VERSION 5.7 ;
  NOWIREEXTENSIONATPIN ON ;
  DIVIDERCHAR "/" ;
  BUSBITCHARS "[]" ;
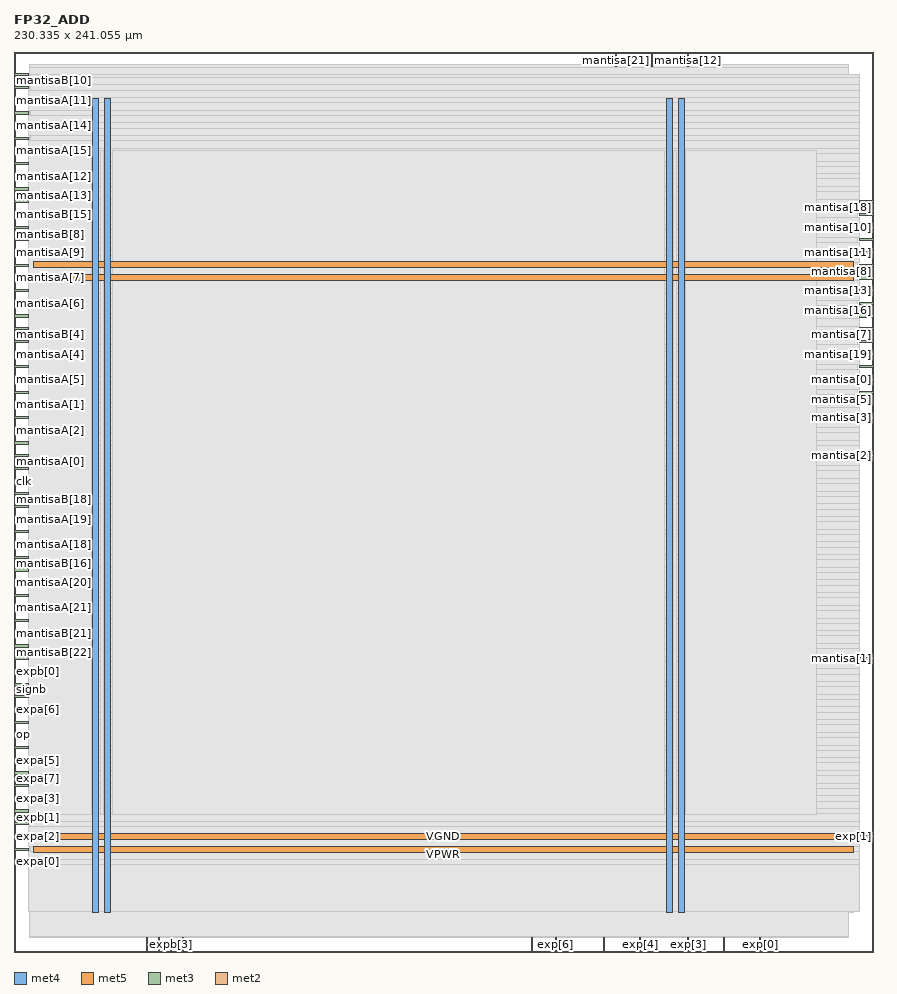
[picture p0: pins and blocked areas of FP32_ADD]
MACRO FP32_ADD
  CLASS BLOCK ;
  FOREIGN FP32_ADD ;
  ORIGIN 0.000 0.000 ;
  SIZE 230.335 BY 241.055 ;
  PIN VGND
    DIRECTION INOUT ;
    USE GROUND ;
    PORT
      LAYER met4 ;
        RECT 24.340 10.640 25.940 228.720 ;
    END
    PORT
      LAYER met4 ;
        RECT 177.940 10.640 179.540 228.720 ;
    END
    PORT
      LAYER met5 ;
        RECT 5.280 30.030 224.720 31.630 ;
    END
    PORT
      LAYER met5 ;
        RECT 5.280 183.210 224.720 184.810 ;
    END
  END VGND
  PIN VPWR
    DIRECTION INOUT ;
    USE POWER ;
    PORT
      LAYER met4 ;
        RECT 21.040 10.640 22.640 228.720 ;
    END
    PORT
      LAYER met4 ;
        RECT 174.640 10.640 176.240 228.720 ;
    END
    PORT
      LAYER met5 ;
        RECT 5.280 26.730 224.720 28.330 ;
    END
    PORT
      LAYER met5 ;
        RECT 5.280 179.910 224.720 181.510 ;
    END
  END VPWR
  PIN clk
    DIRECTION INPUT ;
    USE SIGNAL ;
    ANTENNAGATEAREA 0.852000 ;
    PORT
      LAYER met3 ;
        RECT 0.000 125.840 4.000 126.440 ;
    END
  END clk
  PIN exp[0]
    DIRECTION OUTPUT ;
    USE SIGNAL ;
    ANTENNADIFFAREA 0.445500 ;
    PORT
      LAYER met2 ;
        RECT 199.730 0.000 200.010 4.000 ;
    END
  END exp[0]
  PIN exp[1]
    DIRECTION OUTPUT ;
    USE SIGNAL ;
    ANTENNADIFFAREA 0.445500 ;
    PORT
      LAYER met3 ;
        RECT 226.335 30.640 230.335 31.240 ;
    END
  END exp[1]
  PIN exp[2]
    DIRECTION OUTPUT ;
    USE SIGNAL ;
    ANTENNADIFFAREA 0.445500 ;
    PORT
      LAYER met2 ;
        RECT 190.070 0.000 190.350 4.000 ;
    END
  END exp[2]
  PIN exp[3]
    DIRECTION OUTPUT ;
    USE SIGNAL ;
    ANTENNADIFFAREA 0.445500 ;
    PORT
      LAYER met2 ;
        RECT 180.410 0.000 180.690 4.000 ;
    END
  END exp[3]
  PIN exp[4]
    DIRECTION OUTPUT ;
    USE SIGNAL ;
    ANTENNADIFFAREA 0.445500 ;
    PORT
      LAYER met2 ;
        RECT 167.530 0.000 167.810 4.000 ;
    END
  END exp[4]
  PIN exp[5]
    DIRECTION OUTPUT ;
    USE SIGNAL ;
    ANTENNADIFFAREA 0.445500 ;
    PORT
      LAYER met2 ;
        RECT 157.870 0.000 158.150 4.000 ;
    END
  END exp[5]
  PIN exp[6]
    DIRECTION OUTPUT ;
    USE SIGNAL ;
    ANTENNADIFFAREA 0.445500 ;
    PORT
      LAYER met2 ;
        RECT 144.990 0.000 145.270 4.000 ;
    END
  END exp[6]
  PIN exp[7]
    DIRECTION OUTPUT ;
    USE SIGNAL ;
    ANTENNADIFFAREA 0.445500 ;
    PORT
      LAYER met2 ;
        RECT 138.550 0.000 138.830 4.000 ;
    END
  END exp[7]
  PIN expa[0]
    DIRECTION INPUT ;
    USE SIGNAL ;
    ANTENNAGATEAREA 0.196500 ;
    PORT
      LAYER met3 ;
        RECT 0.000 23.840 4.000 24.440 ;
    END
  END expa[0]
  PIN expa[1]
    DIRECTION INPUT ;
    USE SIGNAL ;
    ANTENNAGATEAREA 0.196500 ;
    PORT
      LAYER met3 ;
        RECT 0.000 27.240 4.000 27.840 ;
    END
  END expa[1]
  PIN expa[2]
    DIRECTION INPUT ;
    USE SIGNAL ;
    ANTENNAGATEAREA 0.196500 ;
    PORT
      LAYER met3 ;
        RECT 0.000 30.640 4.000 31.240 ;
    END
  END expa[2]
  PIN expa[3]
    DIRECTION INPUT ;
    USE SIGNAL ;
    ANTENNAGATEAREA 0.126000 ;
    PORT
      LAYER met3 ;
        RECT 0.000 40.840 4.000 41.440 ;
    END
  END expa[3]
  PIN expa[4]
    DIRECTION INPUT ;
    USE SIGNAL ;
    ANTENNAGATEAREA 0.196500 ;
    PORT
      LAYER met2 ;
        RECT 35.510 0.000 35.790 4.000 ;
    END
  END expa[4]
  PIN expa[5]
    DIRECTION INPUT ;
    USE SIGNAL ;
    ANTENNAGATEAREA 0.196500 ;
    PORT
      LAYER met3 ;
        RECT 0.000 51.040 4.000 51.640 ;
    END
  END expa[5]
  PIN expa[6]
    DIRECTION INPUT ;
    USE SIGNAL ;
    ANTENNAGATEAREA 0.196500 ;
    PORT
      LAYER met3 ;
        RECT 0.000 64.640 4.000 65.240 ;
    END
  END expa[6]
  PIN expa[7]
    DIRECTION INPUT ;
    USE SIGNAL ;
    ANTENNAGATEAREA 0.196500 ;
    PORT
      LAYER met3 ;
        RECT 0.000 44.240 4.000 44.840 ;
    END
  END expa[7]
  PIN expb[0]
    DIRECTION INPUT ;
    USE SIGNAL ;
    ANTENNAGATEAREA 0.196500 ;
    PORT
      LAYER met3 ;
        RECT 0.000 74.840 4.000 75.440 ;
    END
  END expb[0]
  PIN expb[1]
    DIRECTION INPUT ;
    USE SIGNAL ;
    ANTENNAGATEAREA 0.196500 ;
    PORT
      LAYER met3 ;
        RECT 0.000 37.440 4.000 38.040 ;
    END
  END expb[1]
  PIN expb[2]
    DIRECTION INPUT ;
    USE SIGNAL ;
    ANTENNAGATEAREA 0.196500 ;
    PORT
      LAYER met2 ;
        RECT 38.730 0.000 39.010 4.000 ;
    END
  END expb[2]
  PIN expb[3]
    DIRECTION INPUT ;
    USE SIGNAL ;
    ANTENNAGATEAREA 0.196500 ;
    PORT
      LAYER met2 ;
        RECT 41.950 0.000 42.230 4.000 ;
    END
  END expb[3]
  PIN expb[4]
    DIRECTION INPUT ;
    USE SIGNAL ;
    ANTENNAGATEAREA 0.196500 ;
    PORT
      LAYER met2 ;
        RECT 45.170 0.000 45.450 4.000 ;
    END
  END expb[4]
  PIN expb[5]
    DIRECTION INPUT ;
    USE SIGNAL ;
    ANTENNAGATEAREA 0.196500 ;
    PORT
      LAYER met3 ;
        RECT 0.000 54.440 4.000 55.040 ;
    END
  END expb[5]
  PIN expb[6]
    DIRECTION INPUT ;
    USE SIGNAL ;
    ANTENNAGATEAREA 0.196500 ;
    PORT
      LAYER met3 ;
        RECT 0.000 61.240 4.000 61.840 ;
    END
  END expb[6]
  PIN expb[7]
    DIRECTION INPUT ;
    USE SIGNAL ;
    ANTENNAGATEAREA 0.196500 ;
    PORT
      LAYER met3 ;
        RECT 0.000 47.640 4.000 48.240 ;
    END
  END expb[7]
  PIN mantisaA[0]
    DIRECTION INPUT ;
    USE SIGNAL ;
    ANTENNAGATEAREA 0.196500 ;
    PORT
      LAYER met3 ;
        RECT 0.000 129.240 4.000 129.840 ;
    END
  END mantisaA[0]
  PIN mantisaA[10]
    DIRECTION INPUT ;
    USE SIGNAL ;
    ANTENNAGATEAREA 0.126000 ;
    PORT
      LAYER met3 ;
        RECT 0.000 234.640 4.000 235.240 ;
    END
  END mantisaA[10]
  PIN mantisaA[11]
    DIRECTION INPUT ;
    USE SIGNAL ;
    ANTENNAGATEAREA 0.126000 ;
    PORT
      LAYER met3 ;
        RECT 0.000 227.840 4.000 228.440 ;
    END
  END mantisaA[11]
  PIN mantisaA[12]
    DIRECTION INPUT ;
    USE SIGNAL ;
    ANTENNAGATEAREA 0.196500 ;
    PORT
      LAYER met3 ;
        RECT 0.000 207.440 4.000 208.040 ;
    END
  END mantisaA[12]
  PIN mantisaA[13]
    DIRECTION INPUT ;
    USE SIGNAL ;
    ANTENNAGATEAREA 0.196500 ;
    PORT
      LAYER met3 ;
        RECT 0.000 204.040 4.000 204.640 ;
    END
  END mantisaA[13]
  PIN mantisaA[14]
    DIRECTION INPUT ;
    USE SIGNAL ;
    ANTENNAGATEAREA 0.196500 ;
    PORT
      LAYER met3 ;
        RECT 0.000 221.040 4.000 221.640 ;
    END
  END mantisaA[14]
  PIN mantisaA[15]
    DIRECTION INPUT ;
    USE SIGNAL ;
    ANTENNAGATEAREA 0.196500 ;
    PORT
      LAYER met3 ;
        RECT 0.000 214.240 4.000 214.840 ;
    END
  END mantisaA[15]
  PIN mantisaA[16]
    DIRECTION INPUT ;
    USE SIGNAL ;
    ANTENNAGATEAREA 0.196500 ;
    PORT
      LAYER met3 ;
        RECT 0.000 122.440 4.000 123.040 ;
    END
  END mantisaA[16]
  PIN mantisaA[17]
    DIRECTION INPUT ;
    USE SIGNAL ;
    ANTENNAGATEAREA 0.196500 ;
    PORT
      LAYER met3 ;
        RECT 0.000 112.240 4.000 112.840 ;
    END
  END mantisaA[17]
  PIN mantisaA[18]
    DIRECTION INPUT ;
    USE SIGNAL ;
    ANTENNAGATEAREA 0.196500 ;
    PORT
      LAYER met3 ;
        RECT 0.000 108.840 4.000 109.440 ;
    END
  END mantisaA[18]
  PIN mantisaA[19]
    DIRECTION INPUT ;
    USE SIGNAL ;
    ANTENNAGATEAREA 0.196500 ;
    PORT
      LAYER met3 ;
        RECT 0.000 115.640 4.000 116.240 ;
    END
  END mantisaA[19]
  PIN mantisaA[1]
    DIRECTION INPUT ;
    USE SIGNAL ;
    ANTENNAGATEAREA 0.196500 ;
    PORT
      LAYER met3 ;
        RECT 0.000 146.240 4.000 146.840 ;
    END
  END mantisaA[1]
  PIN mantisaA[20]
    DIRECTION INPUT ;
    USE SIGNAL ;
    ANTENNAGATEAREA 0.196500 ;
    PORT
      LAYER met3 ;
        RECT 0.000 98.640 4.000 99.240 ;
    END
  END mantisaA[20]
  PIN mantisaA[21]
    DIRECTION INPUT ;
    USE SIGNAL ;
    ANTENNAGATEAREA 0.196500 ;
    PORT
      LAYER met3 ;
        RECT 0.000 91.840 4.000 92.440 ;
    END
  END mantisaA[21]
  PIN mantisaA[22]
    DIRECTION INPUT ;
    USE SIGNAL ;
    ANTENNAGATEAREA 0.196500 ;
    PORT
      LAYER met3 ;
        RECT 0.000 88.440 4.000 89.040 ;
    END
  END mantisaA[22]
  PIN mantisaA[2]
    DIRECTION INPUT ;
    USE SIGNAL ;
    ANTENNAGATEAREA 0.196500 ;
    PORT
      LAYER met3 ;
        RECT 0.000 139.440 4.000 140.040 ;
    END
  END mantisaA[2]
  PIN mantisaA[3]
    DIRECTION INPUT ;
    USE SIGNAL ;
    ANTENNAGATEAREA 0.196500 ;
    PORT
      LAYER met3 ;
        RECT 0.000 132.640 4.000 133.240 ;
    END
  END mantisaA[3]
  PIN mantisaA[4]
    DIRECTION INPUT ;
    USE SIGNAL ;
    ANTENNAGATEAREA 0.196500 ;
    PORT
      LAYER met3 ;
        RECT 0.000 159.840 4.000 160.440 ;
    END
  END mantisaA[4]
  PIN mantisaA[5]
    DIRECTION INPUT ;
    USE SIGNAL ;
    ANTENNAGATEAREA 0.196500 ;
    PORT
      LAYER met3 ;
        RECT 0.000 153.040 4.000 153.640 ;
    END
  END mantisaA[5]
  PIN mantisaA[6]
    DIRECTION INPUT ;
    USE SIGNAL ;
    ANTENNAGATEAREA 0.196500 ;
    PORT
      LAYER met3 ;
        RECT 0.000 173.440 4.000 174.040 ;
    END
  END mantisaA[6]
  PIN mantisaA[7]
    DIRECTION INPUT ;
    USE SIGNAL ;
    ANTENNAGATEAREA 0.196500 ;
    PORT
      LAYER met3 ;
        RECT 0.000 180.240 4.000 180.840 ;
    END
  END mantisaA[7]
  PIN mantisaA[8]
    DIRECTION INPUT ;
    USE SIGNAL ;
    ANTENNAGATEAREA 0.196500 ;
    PORT
      LAYER met3 ;
        RECT 0.000 183.640 4.000 184.240 ;
    END
  END mantisaA[8]
  PIN mantisaA[9]
    DIRECTION INPUT ;
    USE SIGNAL ;
    ANTENNAGATEAREA 0.196500 ;
    PORT
      LAYER met3 ;
        RECT 0.000 187.040 4.000 187.640 ;
    END
  END mantisaA[9]
  PIN mantisaB[0]
    DIRECTION INPUT ;
    USE SIGNAL ;
    ANTENNAGATEAREA 0.196500 ;
    PORT
      LAYER met3 ;
        RECT 0.000 149.640 4.000 150.240 ;
    END
  END mantisaB[0]
  PIN mantisaB[10]
    DIRECTION INPUT ;
    USE SIGNAL ;
    ANTENNAGATEAREA 0.196500 ;
    PORT
      LAYER met3 ;
        RECT 0.000 231.240 4.000 231.840 ;
    END
  END mantisaB[10]
  PIN mantisaB[11]
    DIRECTION INPUT ;
    USE SIGNAL ;
    ANTENNAGATEAREA 0.196500 ;
    PORT
      LAYER met3 ;
        RECT 0.000 217.640 4.000 218.240 ;
    END
  END mantisaB[11]
  PIN mantisaB[12]
    DIRECTION INPUT ;
    USE SIGNAL ;
    ANTENNAGATEAREA 0.196500 ;
    PORT
      LAYER met3 ;
        RECT 0.000 200.640 4.000 201.240 ;
    END
  END mantisaB[12]
  PIN mantisaB[13]
    DIRECTION INPUT ;
    USE SIGNAL ;
    ANTENNAGATEAREA 0.196500 ;
    PORT
      LAYER met3 ;
        RECT 0.000 210.840 4.000 211.440 ;
    END
  END mantisaB[13]
  PIN mantisaB[14]
    DIRECTION INPUT ;
    USE SIGNAL ;
    ANTENNAGATEAREA 0.196500 ;
    PORT
      LAYER met3 ;
        RECT 0.000 224.440 4.000 225.040 ;
    END
  END mantisaB[14]
  PIN mantisaB[15]
    DIRECTION INPUT ;
    USE SIGNAL ;
    ANTENNAGATEAREA 0.196500 ;
    PORT
      LAYER met3 ;
        RECT 0.000 197.240 4.000 197.840 ;
    END
  END mantisaB[15]
  PIN mantisaB[16]
    DIRECTION INPUT ;
    USE SIGNAL ;
    ANTENNAGATEAREA 0.196500 ;
    PORT
      LAYER met3 ;
        RECT 0.000 102.040 4.000 102.640 ;
    END
  END mantisaB[16]
  PIN mantisaB[17]
    DIRECTION INPUT ;
    USE SIGNAL ;
    ANTENNAGATEAREA 0.196500 ;
    PORT
      LAYER met3 ;
        RECT 0.000 105.440 4.000 106.040 ;
    END
  END mantisaB[17]
  PIN mantisaB[18]
    DIRECTION INPUT ;
    USE SIGNAL ;
    ANTENNAGATEAREA 0.196500 ;
    PORT
      LAYER met3 ;
        RECT 0.000 119.040 4.000 119.640 ;
    END
  END mantisaB[18]
  PIN mantisaB[19]
    DIRECTION INPUT ;
    USE SIGNAL ;
    ANTENNAGATEAREA 0.196500 ;
    PORT
      LAYER met3 ;
        RECT 0.000 95.240 4.000 95.840 ;
    END
  END mantisaB[19]
  PIN mantisaB[1]
    DIRECTION INPUT ;
    USE SIGNAL ;
    ANTENNAGATEAREA 0.196500 ;
    PORT
      LAYER met3 ;
        RECT 0.000 142.840 4.000 143.440 ;
    END
  END mantisaB[1]
  PIN mantisaB[20]
    DIRECTION INPUT ;
    USE SIGNAL ;
    ANTENNAGATEAREA 0.196500 ;
    PORT
      LAYER met3 ;
        RECT 0.000 78.240 4.000 78.840 ;
    END
  END mantisaB[20]
  PIN mantisaB[21]
    DIRECTION INPUT ;
    USE SIGNAL ;
    ANTENNAGATEAREA 0.196500 ;
    PORT
      LAYER met3 ;
        RECT 0.000 85.040 4.000 85.640 ;
    END
  END mantisaB[21]
  PIN mantisaB[22]
    DIRECTION INPUT ;
    USE SIGNAL ;
    ANTENNAGATEAREA 0.196500 ;
    PORT
      LAYER met3 ;
        RECT 0.000 81.640 4.000 82.240 ;
    END
  END mantisaB[22]
  PIN mantisaB[2]
    DIRECTION INPUT ;
    USE SIGNAL ;
    ANTENNAGATEAREA 0.196500 ;
    PORT
      LAYER met3 ;
        RECT 0.000 136.040 4.000 136.640 ;
    END
  END mantisaB[2]
  PIN mantisaB[3]
    DIRECTION INPUT ;
    USE SIGNAL ;
    ANTENNAGATEAREA 0.196500 ;
    PORT
      LAYER met3 ;
        RECT 0.000 156.440 4.000 157.040 ;
    END
  END mantisaB[3]
  PIN mantisaB[4]
    DIRECTION INPUT ;
    USE SIGNAL ;
    ANTENNAGATEAREA 0.196500 ;
    PORT
      LAYER met3 ;
        RECT 0.000 163.240 4.000 163.840 ;
    END
  END mantisaB[4]
  PIN mantisaB[5]
    DIRECTION INPUT ;
    USE SIGNAL ;
    ANTENNAGATEAREA 0.196500 ;
    PORT
      LAYER met3 ;
        RECT 0.000 166.640 4.000 167.240 ;
    END
  END mantisaB[5]
  PIN mantisaB[6]
    DIRECTION INPUT ;
    USE SIGNAL ;
    ANTENNAGATEAREA 0.196500 ;
    PORT
      LAYER met3 ;
        RECT 0.000 170.040 4.000 170.640 ;
    END
  END mantisaB[6]
  PIN mantisaB[7]
    DIRECTION INPUT ;
    USE SIGNAL ;
    ANTENNAGATEAREA 0.196500 ;
    PORT
      LAYER met3 ;
        RECT 0.000 176.840 4.000 177.440 ;
    END
  END mantisaB[7]
  PIN mantisaB[8]
    DIRECTION INPUT ;
    USE SIGNAL ;
    ANTENNAGATEAREA 0.196500 ;
    PORT
      LAYER met3 ;
        RECT 0.000 193.840 4.000 194.440 ;
    END
  END mantisaB[8]
  PIN mantisaB[9]
    DIRECTION INPUT ;
    USE SIGNAL ;
    ANTENNAGATEAREA 0.196500 ;
    PORT
      LAYER met3 ;
        RECT 0.000 190.440 4.000 191.040 ;
    END
  END mantisaB[9]
  PIN mantisa[0]
    DIRECTION OUTPUT ;
    USE SIGNAL ;
    ANTENNADIFFAREA 0.445500 ;
    PORT
      LAYER met3 ;
        RECT 226.335 153.040 230.335 153.640 ;
    END
  END mantisa[0]
  PIN mantisa[10]
    DIRECTION OUTPUT ;
    USE SIGNAL ;
    ANTENNADIFFAREA 0.445500 ;
    PORT
      LAYER met3 ;
        RECT 226.335 193.840 230.335 194.440 ;
    END
  END mantisa[10]
  PIN mantisa[11]
    DIRECTION OUTPUT ;
    USE SIGNAL ;
    ANTENNADIFFAREA 0.445500 ;
    PORT
      LAYER met3 ;
        RECT 226.335 187.040 230.335 187.640 ;
    END
  END mantisa[11]
  PIN mantisa[12]
    DIRECTION OUTPUT ;
    USE SIGNAL ;
    ANTENNADIFFAREA 0.445500 ;
    PORT
      LAYER met2 ;
        RECT 180.410 237.055 180.690 241.055 ;
    END
  END mantisa[12]
  PIN mantisa[13]
    DIRECTION OUTPUT ;
    USE SIGNAL ;
    ANTENNADIFFAREA 0.445500 ;
    PORT
      LAYER met3 ;
        RECT 226.335 176.840 230.335 177.440 ;
    END
  END mantisa[13]
  PIN mantisa[14]
    DIRECTION OUTPUT ;
    USE SIGNAL ;
    ANTENNADIFFAREA 0.445500 ;
    PORT
      LAYER met3 ;
        RECT 226.335 200.640 230.335 201.240 ;
    END
  END mantisa[14]
  PIN mantisa[15]
    DIRECTION OUTPUT ;
    USE SIGNAL ;
    ANTENNADIFFAREA 0.445500 ;
    PORT
      LAYER met3 ;
        RECT 226.335 190.440 230.335 191.040 ;
    END
  END mantisa[15]
  PIN mantisa[16]
    DIRECTION OUTPUT ;
    USE SIGNAL ;
    ANTENNADIFFAREA 0.445500 ;
    PORT
      LAYER met3 ;
        RECT 226.335 173.440 230.335 174.040 ;
    END
  END mantisa[16]
  PIN mantisa[17]
    DIRECTION OUTPUT ;
    USE SIGNAL ;
    ANTENNADIFFAREA 0.445500 ;
    PORT
      LAYER met3 ;
        RECT 226.335 170.040 230.335 170.640 ;
    END
  END mantisa[17]
  PIN mantisa[18]
    DIRECTION OUTPUT ;
    USE SIGNAL ;
    ANTENNADIFFAREA 0.445500 ;
    PORT
      LAYER met3 ;
        RECT 226.335 197.240 230.335 197.840 ;
    END
  END mantisa[18]
  PIN mantisa[19]
    DIRECTION OUTPUT ;
    USE SIGNAL ;
    ANTENNADIFFAREA 0.445500 ;
    PORT
      LAYER met3 ;
        RECT 226.335 159.840 230.335 160.440 ;
    END
  END mantisa[19]
  PIN mantisa[1]
    DIRECTION OUTPUT ;
    USE SIGNAL ;
    ANTENNADIFFAREA 0.445500 ;
    PORT
      LAYER met3 ;
        RECT 226.335 78.240 230.335 78.840 ;
    END
  END mantisa[1]
  PIN mantisa[20]
    DIRECTION OUTPUT ;
    USE SIGNAL ;
    ANTENNADIFFAREA 0.445500 ;
    PORT
      LAYER met2 ;
        RECT 170.750 237.055 171.030 241.055 ;
    END
  END mantisa[20]
  PIN mantisa[21]
    DIRECTION OUTPUT ;
    USE SIGNAL ;
    ANTENNADIFFAREA 0.445500 ;
    PORT
      LAYER met2 ;
        RECT 161.090 237.055 161.370 241.055 ;
    END
  END mantisa[21]
  PIN mantisa[22]
    DIRECTION OUTPUT ;
    USE SIGNAL ;
    ANTENNADIFFAREA 0.445500 ;
    PORT
      LAYER met2 ;
        RECT 164.310 237.055 164.590 241.055 ;
    END
  END mantisa[22]
  PIN mantisa[2]
    DIRECTION OUTPUT ;
    USE SIGNAL ;
    ANTENNADIFFAREA 0.445500 ;
    PORT
      LAYER met3 ;
        RECT 226.335 132.640 230.335 133.240 ;
    END
  END mantisa[2]
  PIN mantisa[3]
    DIRECTION OUTPUT ;
    USE SIGNAL ;
    ANTENNADIFFAREA 0.445500 ;
    PORT
      LAYER met3 ;
        RECT 226.335 142.840 230.335 143.440 ;
    END
  END mantisa[3]
  PIN mantisa[4]
    DIRECTION OUTPUT ;
    USE SIGNAL ;
    ANTENNADIFFAREA 0.445500 ;
    PORT
      LAYER met3 ;
        RECT 226.335 183.640 230.335 184.240 ;
    END
  END mantisa[4]
  PIN mantisa[5]
    DIRECTION OUTPUT ;
    USE SIGNAL ;
    ANTENNADIFFAREA 0.445500 ;
    PORT
      LAYER met3 ;
        RECT 226.335 149.640 230.335 150.240 ;
    END
  END mantisa[5]
  PIN mantisa[6]
    DIRECTION OUTPUT ;
    USE SIGNAL ;
    ANTENNADIFFAREA 0.445500 ;
    PORT
      LAYER met3 ;
        RECT 226.335 166.640 230.335 167.240 ;
    END
  END mantisa[6]
  PIN mantisa[7]
    DIRECTION OUTPUT ;
    USE SIGNAL ;
    ANTENNADIFFAREA 0.445500 ;
    PORT
      LAYER met3 ;
        RECT 226.335 163.240 230.335 163.840 ;
    END
  END mantisa[7]
  PIN mantisa[8]
    DIRECTION OUTPUT ;
    USE SIGNAL ;
    ANTENNADIFFAREA 0.445500 ;
    PORT
      LAYER met3 ;
        RECT 226.335 180.240 230.335 180.840 ;
    END
  END mantisa[8]
  PIN mantisa[9]
    DIRECTION OUTPUT ;
    USE SIGNAL ;
    ANTENNADIFFAREA 0.445500 ;
    PORT
      LAYER met3 ;
        RECT 226.335 156.440 230.335 157.040 ;
    END
  END mantisa[9]
  PIN op
    DIRECTION INPUT ;
    USE SIGNAL ;
    ANTENNAGATEAREA 0.196500 ;
    PORT
      LAYER met3 ;
        RECT 0.000 57.840 4.000 58.440 ;
    END
  END op
  PIN sign
    DIRECTION OUTPUT ;
    USE SIGNAL ;
    ANTENNADIFFAREA 0.445500 ;
    PORT
      LAYER met3 ;
        RECT 0.000 34.040 4.000 34.640 ;
    END
  END sign
  PIN signa
    DIRECTION INPUT ;
    USE SIGNAL ;
    ANTENNAGATEAREA 0.196500 ;
    PORT
      LAYER met3 ;
        RECT 0.000 71.440 4.000 72.040 ;
    END
  END signa
  PIN signb
    DIRECTION INPUT ;
    USE SIGNAL ;
    ANTENNAGATEAREA 0.196500 ;
    PORT
      LAYER met3 ;
        RECT 0.000 68.040 4.000 68.640 ;
    END
  END signb
  OBS
      LAYER nwell ;
        RECT 5.330 10.795 224.670 228.565 ;
      LAYER li1 ;
        RECT 5.520 10.795 224.480 228.565 ;
      LAYER met1 ;
        RECT 4.210 10.640 224.780 228.720 ;
      LAYER met2 ;
        RECT 4.230 236.775 160.810 237.730 ;
        RECT 161.650 236.775 164.030 237.730 ;
        RECT 164.870 236.775 170.470 237.730 ;
        RECT 171.310 236.775 180.130 237.730 ;
        RECT 180.970 236.775 223.470 237.730 ;
        RECT 4.230 4.280 223.470 236.775 ;
        RECT 4.230 4.000 35.230 4.280 ;
        RECT 36.070 4.000 38.450 4.280 ;
        RECT 39.290 4.000 41.670 4.280 ;
        RECT 42.510 4.000 44.890 4.280 ;
        RECT 45.730 4.000 138.270 4.280 ;
        RECT 139.110 4.000 144.710 4.280 ;
        RECT 145.550 4.000 157.590 4.280 ;
        RECT 158.430 4.000 167.250 4.280 ;
        RECT 168.090 4.000 180.130 4.280 ;
        RECT 180.970 4.000 189.790 4.280 ;
        RECT 190.630 4.000 199.450 4.280 ;
        RECT 200.290 4.000 223.470 4.280 ;
      LAYER met3 ;
        RECT 4.400 234.240 226.335 235.105 ;
        RECT 3.750 232.240 226.335 234.240 ;
        RECT 4.400 230.840 226.335 232.240 ;
        RECT 3.750 228.840 226.335 230.840 ;
        RECT 4.400 227.440 226.335 228.840 ;
        RECT 3.750 225.440 226.335 227.440 ;
        RECT 4.400 224.040 226.335 225.440 ;
        RECT 3.750 222.040 226.335 224.040 ;
        RECT 4.400 220.640 226.335 222.040 ;
        RECT 3.750 218.640 226.335 220.640 ;
        RECT 4.400 217.240 226.335 218.640 ;
        RECT 3.750 215.240 226.335 217.240 ;
        RECT 4.400 213.840 226.335 215.240 ;
        RECT 3.750 211.840 226.335 213.840 ;
        RECT 4.400 210.440 226.335 211.840 ;
        RECT 3.750 208.440 226.335 210.440 ;
        RECT 4.400 207.040 226.335 208.440 ;
        RECT 3.750 205.040 226.335 207.040 ;
        RECT 4.400 203.640 226.335 205.040 ;
        RECT 3.750 201.640 226.335 203.640 ;
        RECT 4.400 200.240 225.935 201.640 ;
        RECT 3.750 198.240 226.335 200.240 ;
        RECT 4.400 196.840 225.935 198.240 ;
        RECT 3.750 194.840 226.335 196.840 ;
        RECT 4.400 193.440 225.935 194.840 ;
        RECT 3.750 191.440 226.335 193.440 ;
        RECT 4.400 190.040 225.935 191.440 ;
        RECT 3.750 188.040 226.335 190.040 ;
        RECT 4.400 186.640 225.935 188.040 ;
        RECT 3.750 184.640 226.335 186.640 ;
        RECT 4.400 183.240 225.935 184.640 ;
        RECT 3.750 181.240 226.335 183.240 ;
        RECT 4.400 179.840 225.935 181.240 ;
        RECT 3.750 177.840 226.335 179.840 ;
        RECT 4.400 176.440 225.935 177.840 ;
        RECT 3.750 174.440 226.335 176.440 ;
        RECT 4.400 173.040 225.935 174.440 ;
        RECT 3.750 171.040 226.335 173.040 ;
        RECT 4.400 169.640 225.935 171.040 ;
        RECT 3.750 167.640 226.335 169.640 ;
        RECT 4.400 166.240 225.935 167.640 ;
        RECT 3.750 164.240 226.335 166.240 ;
        RECT 4.400 162.840 225.935 164.240 ;
        RECT 3.750 160.840 226.335 162.840 ;
        RECT 4.400 159.440 225.935 160.840 ;
        RECT 3.750 157.440 226.335 159.440 ;
        RECT 4.400 156.040 225.935 157.440 ;
        RECT 3.750 154.040 226.335 156.040 ;
        RECT 4.400 152.640 225.935 154.040 ;
        RECT 3.750 150.640 226.335 152.640 ;
        RECT 4.400 149.240 225.935 150.640 ;
        RECT 3.750 147.240 226.335 149.240 ;
        RECT 4.400 145.840 226.335 147.240 ;
        RECT 3.750 143.840 226.335 145.840 ;
        RECT 4.400 142.440 225.935 143.840 ;
        RECT 3.750 140.440 226.335 142.440 ;
        RECT 4.400 139.040 226.335 140.440 ;
        RECT 3.750 137.040 226.335 139.040 ;
        RECT 4.400 135.640 226.335 137.040 ;
        RECT 3.750 133.640 226.335 135.640 ;
        RECT 4.400 132.240 225.935 133.640 ;
        RECT 3.750 130.240 226.335 132.240 ;
        RECT 4.400 128.840 226.335 130.240 ;
        RECT 3.750 126.840 226.335 128.840 ;
        RECT 4.400 125.440 226.335 126.840 ;
        RECT 3.750 123.440 226.335 125.440 ;
        RECT 4.400 122.040 226.335 123.440 ;
        RECT 3.750 120.040 226.335 122.040 ;
        RECT 4.400 118.640 226.335 120.040 ;
        RECT 3.750 116.640 226.335 118.640 ;
        RECT 4.400 115.240 226.335 116.640 ;
        RECT 3.750 113.240 226.335 115.240 ;
        RECT 4.400 111.840 226.335 113.240 ;
        RECT 3.750 109.840 226.335 111.840 ;
        RECT 4.400 108.440 226.335 109.840 ;
        RECT 3.750 106.440 226.335 108.440 ;
        RECT 4.400 105.040 226.335 106.440 ;
        RECT 3.750 103.040 226.335 105.040 ;
        RECT 4.400 101.640 226.335 103.040 ;
        RECT 3.750 99.640 226.335 101.640 ;
        RECT 4.400 98.240 226.335 99.640 ;
        RECT 3.750 96.240 226.335 98.240 ;
        RECT 4.400 94.840 226.335 96.240 ;
        RECT 3.750 92.840 226.335 94.840 ;
        RECT 4.400 91.440 226.335 92.840 ;
        RECT 3.750 89.440 226.335 91.440 ;
        RECT 4.400 88.040 226.335 89.440 ;
        RECT 3.750 86.040 226.335 88.040 ;
        RECT 4.400 84.640 226.335 86.040 ;
        RECT 3.750 82.640 226.335 84.640 ;
        RECT 4.400 81.240 226.335 82.640 ;
        RECT 3.750 79.240 226.335 81.240 ;
        RECT 4.400 77.840 225.935 79.240 ;
        RECT 3.750 75.840 226.335 77.840 ;
        RECT 4.400 74.440 226.335 75.840 ;
        RECT 3.750 72.440 226.335 74.440 ;
        RECT 4.400 71.040 226.335 72.440 ;
        RECT 3.750 69.040 226.335 71.040 ;
        RECT 4.400 67.640 226.335 69.040 ;
        RECT 3.750 65.640 226.335 67.640 ;
        RECT 4.400 64.240 226.335 65.640 ;
        RECT 3.750 62.240 226.335 64.240 ;
        RECT 4.400 60.840 226.335 62.240 ;
        RECT 3.750 58.840 226.335 60.840 ;
        RECT 4.400 57.440 226.335 58.840 ;
        RECT 3.750 55.440 226.335 57.440 ;
        RECT 4.400 54.040 226.335 55.440 ;
        RECT 3.750 52.040 226.335 54.040 ;
        RECT 4.400 50.640 226.335 52.040 ;
        RECT 3.750 48.640 226.335 50.640 ;
        RECT 4.400 47.240 226.335 48.640 ;
        RECT 3.750 45.240 226.335 47.240 ;
        RECT 4.400 43.840 226.335 45.240 ;
        RECT 3.750 41.840 226.335 43.840 ;
        RECT 4.400 40.440 226.335 41.840 ;
        RECT 3.750 38.440 226.335 40.440 ;
        RECT 4.400 37.040 226.335 38.440 ;
        RECT 3.750 35.040 226.335 37.040 ;
        RECT 4.400 33.640 226.335 35.040 ;
        RECT 3.750 31.640 226.335 33.640 ;
        RECT 4.400 30.240 225.935 31.640 ;
        RECT 3.750 28.240 226.335 30.240 ;
        RECT 4.400 26.840 226.335 28.240 ;
        RECT 3.750 24.840 226.335 26.840 ;
        RECT 4.400 23.440 226.335 24.840 ;
        RECT 3.750 10.715 226.335 23.440 ;
      LAYER met4 ;
        RECT 3.975 36.895 20.640 214.705 ;
        RECT 23.040 36.895 23.940 214.705 ;
        RECT 26.340 36.895 174.240 214.705 ;
        RECT 176.640 36.895 177.540 214.705 ;
        RECT 179.940 36.895 214.985 214.705 ;
  END
END FP32_ADD
END LIBRARY

